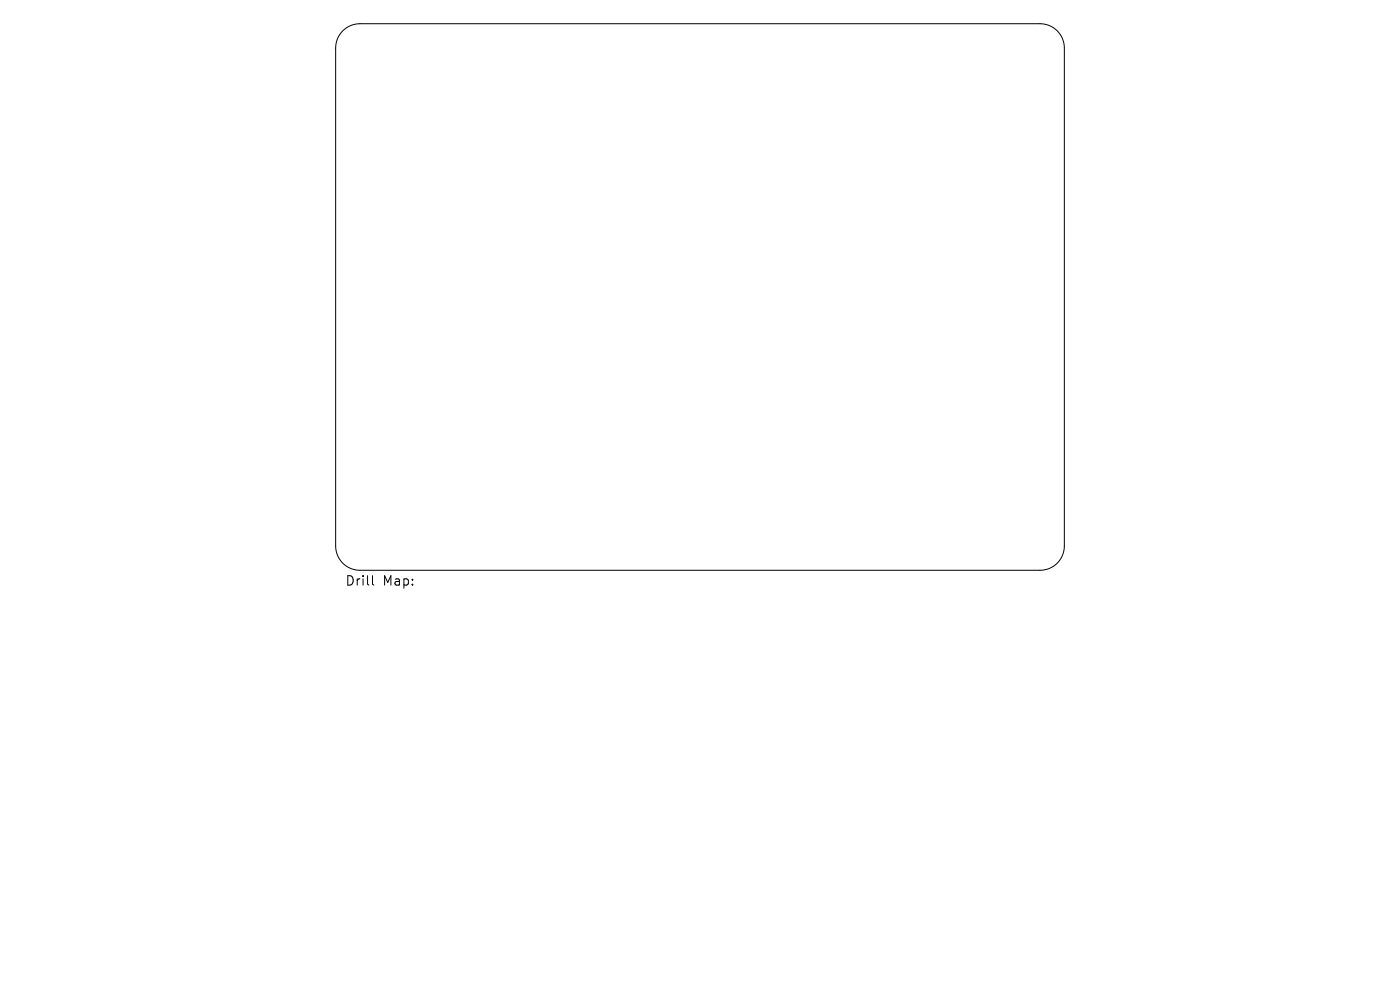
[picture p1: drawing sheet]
<svg xmlns="http://www.w3.org/2000/svg" width="297mm" height="210mm" viewBox="0 0 297 210" stroke-linecap="round" stroke-linejoin="round" font-family="sans-serif">
<defs><g id="words">
<g font-size="2.8">
<text x="73.2" y="124.5">Drill</text>
<text x="81.2" y="124.5">Map:</text>
</g>
</g></defs>
<path d="M72.7 6.5a5.2 5.2 0 0 1 3.7-1.5h144.2a5.2 5.2 0 0 1 5.2 5.2v105.6a5.2 5.2 0 0 1-5.2 5.2h-144.2a5.2 5.2 0 0 1-5.2-5.2v-105.6a5.2 5.2 0 0 1 1.5-3.7zM79 122.1v1.7l.3 .3" fill="none" stroke="#000" stroke-width=".21"/>
<use href="#words"/>
</svg>
